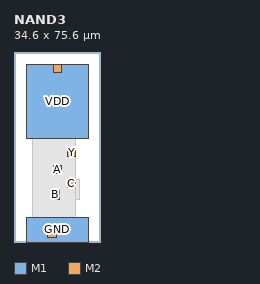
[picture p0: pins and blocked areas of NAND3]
MACRO NAND3
  CLASS CORE ;
  ORIGIN 0 0 ;
  SIZE 34.600 BY 75.600 ;
  SYMMETRY X Y ;
  SITE TR1um_access_site ;
  PIN VDD
    DIRECTION INOUT ;
    USE POWER ;
    PORT
      LAYER M1 ;
        RECT 5.000 41.000 29.600 70.800 ;
      LAYER M2 ;
        RECT 15.600 67.400 19.000 70.800 ;
    END
  END VDD
  PIN GND
    DIRECTION INOUT ;
    USE GROUND ;
    PORT
      LAYER M1 ;
        RECT 5.000 0.000 29.600 9.800 ;
      LAYER M2 ;
        RECT 13.400 1.600 16.800 5.000 ;
    END
  END GND
  PIN A
    DIRECTION INPUT ;
    USE SIGNAL ;
    PORT
      LAYER M2 ;
        RECT 15.600 27.100 19.000 30.500 ;
    END
  END A
  PIN B
    DIRECTION INPUT ;
    USE SIGNAL ;
    PORT
      LAYER M2 ;
        RECT 14.800 17.100 18.200 20.500 ;
    END
  END B
  PIN C
    DIRECTION INPUT ;
    USE SIGNAL ;
    PORT
      LAYER M2 ;
        RECT 21.100 21.550 24.500 24.950 ;
    END
  END C
  PIN Y
    DIRECTION OUTPUT ;
    USE SIGNAL ;
    PORT
      LAYER M2 ;
        RECT 21.200 33.900 24.600 37.300 ;
    END
  END Y
  OBS
    LAYER M1 ;
      RECT 13.100 6.400 15.700 9.800 ;
    LAYER M1 ;
      RECT 17.100 6.400 19.700 9.800 ;
    LAYER M1 ;
      RECT 12.000 14.600 19.000 20.500 ;
    LAYER M1 ;
      RECT 21.100 16.950 26.000 25.000 ;
    LAYER M1 ;
      RECT 10.700 27.100 19.000 35.800 ;
    LAYER M1 ;
      RECT 7.300 6.400 24.600 51.200 ;
    LAYER V1 ;
      RECT 14.400 2.600 15.800 4.000 ;
    LAYER V1 ;
      RECT 15.800 18.100 17.200 19.500 ;
    LAYER V1 ;
      RECT 22.100 22.550 23.500 23.950 ;
    LAYER V1 ;
      RECT 16.600 28.100 18.000 29.500 ;
    LAYER V1 ;
      RECT 22.200 34.900 23.600 36.300 ;
    LAYER V1 ;
      RECT 16.600 68.400 18.000 69.800 ;
  END
END NAND3
